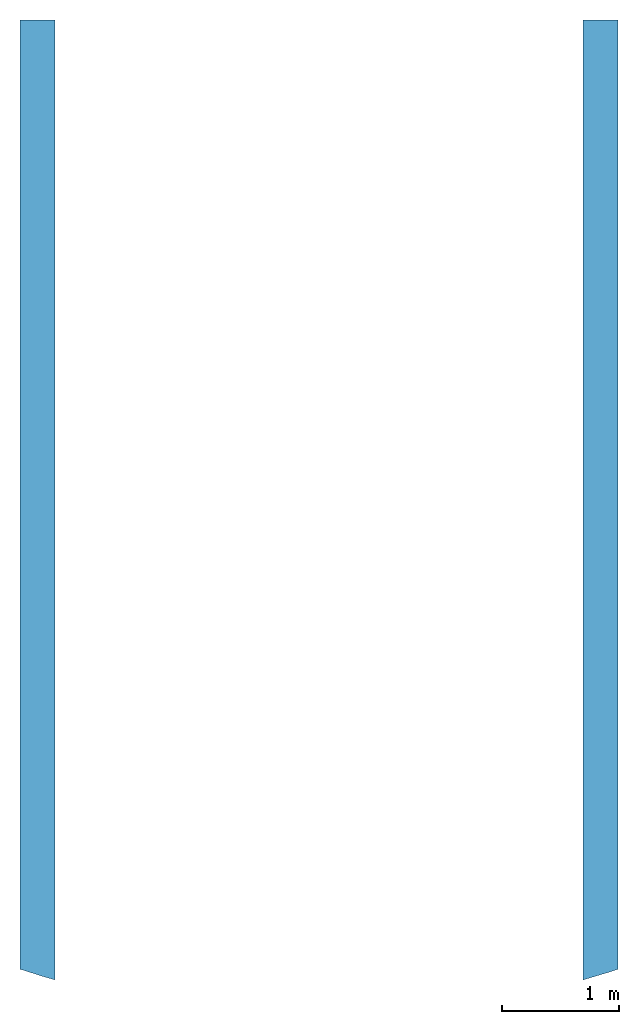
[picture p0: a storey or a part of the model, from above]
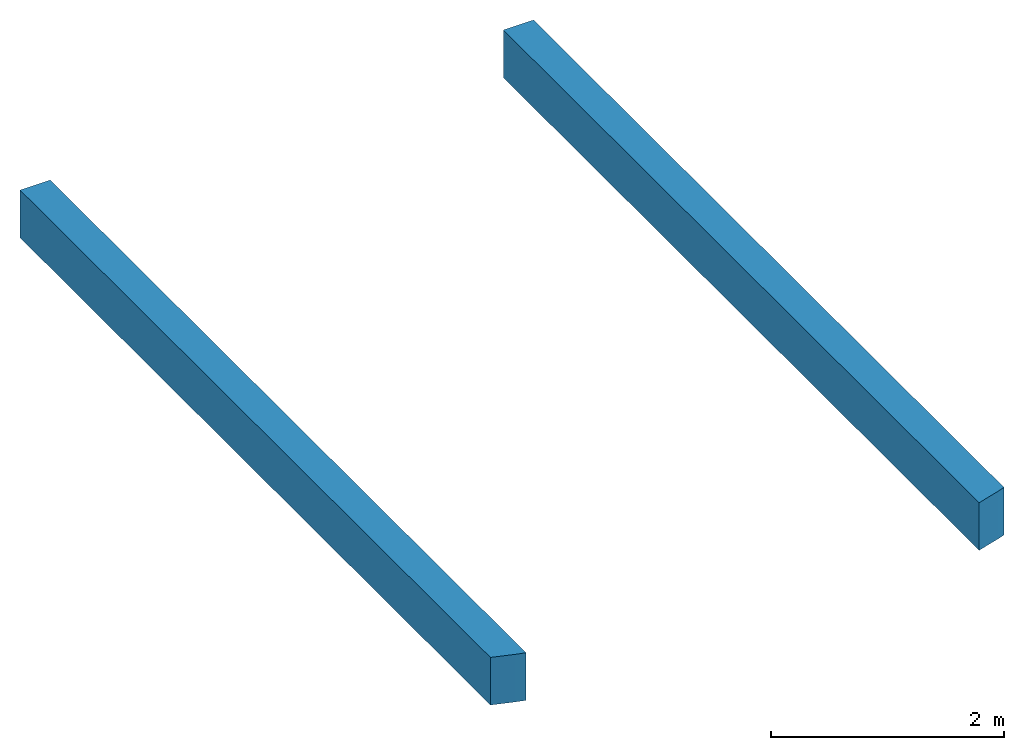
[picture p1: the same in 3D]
Properties of the parts of a building model (IFC4)

# File
Description: ViewDefinition [Design_Transfer_View, QuantityTakeOffAddOnView, SpaceBoundary2ndLevelAddOnView], ExchangeRequirement [Architecture], Option [Elements to export: Visible elements (on all stories)], Option [Partial Structure Display: Entire Model], Option [IFC Domain: All], Option [Structural Function: All Elements], Option [Convert Grid elements: On], Option [Convert IFC Annotations and Archicad 2D elements: Off], Option [Convert 2D symbols of Doors and Windows: Off], Option [Export geometries that Participates in Collision Detection only: Off], Option [Split complex elements: Off], Option [Material Preservation: Explode where necessary], Option [Elements in Solid Element Operations: Extruded/revolved], Option [Elements with junctions: Extruded/revolved without junctions], Option [IFC Model position: Survey Point and Project Origin], Option [Curtain Wall export mode: Container Element], Option [Railing export mode: Single Element], Option [Stair export mode: Container Element], Option [Properties To Export: All properties], Option [Space containment: On], Option [IFC Domain For Space Containment: All], Option [Geometry to type objects: Off], Option [Element Properties: Off], Option [Building Material Properties: Off], Option [Element Parameters: Off], Option [Component Parameters: Off], Option [IFC Base Quantities: On], Option [Door Window Parameters: On], Option [IFC Space boundaries: On], Option [Archicad Zone Categories as IFC Space classification data: Off], Option [Element Classifications: Off]
File name: C:\Users\micel\OneDrive\Dokumenty\ŠKOLA\!!4.LS!!\BAKALÁŘKA\Publikace\Nová složka\_LES24-PST-03-M3-Stropni_deska_nad_boulderem.ifc
Time: 2024-05-21T14:06:42
Author: Architect
Organization: Building Designer Office
Written by: DDS_IFC v3.0
Made in: IFC file generated by Graphisoft Archicad 27.0.0 CZE FULL Windows version (IFC add-on version: 3001 CZE FULL).
Authorization: The authorising person

# IfcProject, Univerzitní lezecké centrum
Description: BIM projekt - bakalářská práce

# IfcSite, Exteriér
RefLatitude: 50, 1, 18, 339575; RefLongitude: 15, 46, 11, 568244; RefElevation: 221783 mm
Qto_SiteBaseQuantities - GrossPerimeter: 0 mm; GrossArea: 3562 m2

# IfcBuilding, Univerzitní lezecké centrum
Qto_BuildingBaseQuantities - GrossFloorArea: 0 m2

# IfcBuildingStorey (2)
In: Univerzitní lezecké centrum
Qto_BuildingStoreyBaseQuantities - NetHeight: 3200 mm; GrossHeight: 3200 mm; GrossFloorArea: 0 m2
Name | Elevation (mm)
3.NP | 6400
4.NP | 9600

# IfcBeam: Beton vyztužený průvlak boulderu 300 x 500 (2)
In: 3.NP
Type - PredefinedType: BEAM
Material: Beton vyztužený průvlak boulderu
Pset_BeamCommon - Span: 8185.82 mm; Slope: 0 deg; Status: EXISTING; LoadBearing: yes; Reference: Beton vyztužený průvlak boulderu 300 x 500
Pset_ManufacturerOccurrence - AcquisitionDate: DD.MM.RRRR
Qto_BeamBaseQuantities - CrossSectionArea: 0.15 m2; GrossVolume: 1.22787 m3; NetVolume: 1.22112 m3
Name | Length (mm) | OuterSurfaceArea (m2) | GrossSurfaceArea (m2) = NetSurfaceArea (m2)
T017 | 8185.43 | 13.0241 | 13.3241
T016 | 8185.82 | 13.0242 | 13.3242

# IfcSlab: Beton vyztužený strop nad boulderem 200 (2)
In: 4.NP
Type - PredefinedType: FLOOR
Material: Beton vyztužený strop nad boulderem 200 mm
Pset_SlabCommon - Status: EXISTING; LoadBearing: yes
Pset_ManufacturerOccurrence - AcquisitionDate: DD.MM.RRRR
Qto_SlabBaseQuantities - Width: 200 mm; Beton vyztužený strop nad boulderem, Width: 200 mm
Name | Perimeter (mm) | GrossArea (m2) | NetArea (m2) | GrossVolume (m3) | NetVolume (m3)
D05 | 47324.5 | 72.7245 | 72.7245 | 14.5449 | 14.5449
D06 | 42761.1 | 110.551 | 103.869 | 22.1074 | 20.771
